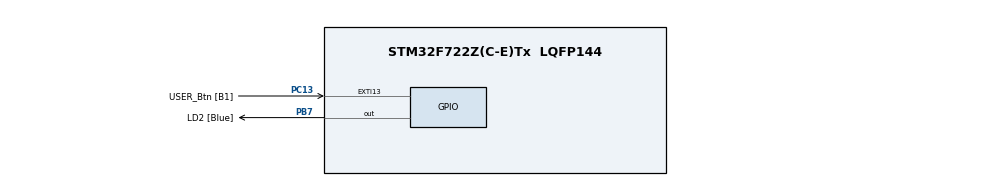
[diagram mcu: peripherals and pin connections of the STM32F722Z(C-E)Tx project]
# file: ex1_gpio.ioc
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Mcu.Family=STM32F7
Mcu.Name=STM32F722Z(C-E)Tx
Mcu.Package=LQFP144
NVIC.PriorityGroup=NVIC_PRIORITYGROUP_4
NVIC.TIM1_UP_TIM10_IRQn=true\:0\:0\:false\:false\:true\:false\:false
NVIC.TimeBase=TIM1_UP_TIM10_IRQn
NVIC.TimeBaseIP=TIM1
PB3.GPIO_Label=SWO
PB3.Signal=SYS_JTDO-SWO
PB7.GPIO_Label=LD2 [Blue]
PB7.Signal=GPIO_Output
PC13.GPIO_Label=USER_Btn [B1]
PC13.Signal=GPXTI13
ProjectManager.HeapSize=0x200
ProjectManager.StackSize=0x400
ProjectManager.TargetToolchain=SW4STM32
RCC.48MHZClocksFreq_Value=24000000
RCC.AHBFreq_Value=108000000
RCC.APB1CLKDivider=RCC_HCLK_DIV4
RCC.APB1Freq_Value=27000000
RCC.APB1TimFreq_Value=54000000
RCC.APB2CLKDivider=RCC_HCLK_DIV2
RCC.APB2Freq_Value=54000000
RCC.APB2TimFreq_Value=108000000
RCC.CortexFreq_Value=108000000
RCC.HCLKFreq_Value=108000000
RCC.HSE_VALUE=25000000
RCC.HSI_VALUE=16000000
RCC.PLLM=25
RCC.PLLMUL=RCC_PLL_MUL9
RCC.PLLN=432
RCC.PLLP=RCC_PLLP_DIV4
RCC.PLLQ=9
RCC.PRESCALERUSB=RCC_USBCLKSOURCE_PLL_DIV1_5
RCC.SYSCLKFreq_VALUE=108000000
RCC.SYSCLKSource=RCC_SYSCLKSOURCE_PLLCLK
RCC.SYSCLKSourceVirtual=RCC_SYSCLKSOURCE_PLLCLK
RCC.USBFreq_Value=48000000
RCC.VCOOutputFreq_Value=432000000
board=NUCLEO-F722ZE

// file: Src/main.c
/**
  ******************************************************************************
  * @file           : main.c
  * @brief          : Main program body
  ******************************************************************************
  ** This notice applies to any and all portions of this file
  * that are not between comment pairs USER CODE BEGIN and
  * USER CODE END. Other portions of this file, whether
  * inserted by the user or by software development tools
  * are owned by their respective copyright owners.
  *
  * COPYRIGHT(c) 2018 STMicroelectronics
  *
  * Redistribution and use in source and binary forms, with or without modification,
  * are permitted provided that the following conditions are met:
  *   1. Redistributions of source code must retain the above copyright notice,
  *      this list of conditions and the following disclaimer.
  *   2. Redistributions in binary form must reproduce the above copyright notice,
  *      this list of conditions and the following disclaimer in the documentation
  *      and/or other materials provided with the distribution.
  *   3. Neither the name of STMicroelectronics nor the names of its contributors
  *      may be used to endorse or promote products derived from this software
  *      without specific prior written permission.
  *
  * THIS SOFTWARE IS PROVIDED BY THE COPYRIGHT HOLDERS AND CONTRIBUTORS "AS IS"
  * AND ANY EXPRESS OR IMPLIED WARRANTIES, INCLUDING, BUT NOT LIMITED TO, THE
  * IMPLIED WARRANTIES OF MERCHANTABILITY AND FITNESS FOR A PARTICULAR PURPOSE ARE
  * DISCLAIMED. IN NO EVENT SHALL THE COPYRIGHT HOLDER OR CONTRIBUTORS BE LIABLE
  * FOR ANY DIRECT, INDIRECT, INCIDENTAL, SPECIAL, EXEMPLARY, OR CONSEQUENTIAL
  * DAMAGES (INCLUDING, BUT NOT LIMITED TO, PROCUREMENT OF SUBSTITUTE GOODS OR
  * SERVICES; LOSS OF USE, DATA, OR PROFITS; OR BUSINESS INTERRUPTION) HOWEVER
  * CAUSED AND ON ANY THEORY OF LIABILITY, WHETHER IN CONTRACT, STRICT LIABILITY,
  * OR TORT (INCLUDING NEGLIGENCE OR OTHERWISE) ARISING IN ANY WAY OUT OF THE USE
  * OF THIS SOFTWARE, EVEN IF ADVISED OF THE POSSIBILITY OF SUCH DAMAGE.
  *
  ******************************************************************************
  */
#include "main.h"
#include "stm32f7xx_hal.h"

/* USER CODE BEGIN PV */
/* Private variables ---------------------------------------------------------*/

/* USER CODE END PV */

void SystemClock_Config(void);
static void MX_GPIO_Init(void);

/* USER CODE BEGIN PFP */
/* Private function prototypes -----------------------------------------------*/

/* USER CODE END PFP */

int main(void)
{

  /* MCU Configuration----------------------------------------------------------*/

  /* Reset of all peripherals, Initializes the Flash interface and the Systick. */
  HAL_Init();

  /* Configure the system clock */
  SystemClock_Config();

  /* Initialize all configured peripherals */
  MX_GPIO_Init();
  /* USER CODE BEGIN 2 */
  __HAL_RCC_GPIOB_CLK_ENABLE();
  volatile uint32_t* GPIOB_MODER	= (uint32_t*)	0x40020400;
  volatile uint32_t* GPIOB_ODR		= (uint32_t*)	(0x40020400 + 0x14);
  /* USER CODE END 2 */
  *GPIOB_MODER  |= 0x200;
  *GPIOB_ODR	|= 0x80;
  /* Infinite loop */
  /* USER CODE BEGIN WHILE */

  while (1)
  {
	  *GPIOB_ODR	|= 0x80;
	  HAL_Delay(9000);
	  *GPIOB_ODR	&= 0x00;
  /* USER CODE END WHILE */

  }

}

void SystemClock_Config(void)
{

  RCC_OscInitTypeDef RCC_OscInitStruct;
  RCC_ClkInitTypeDef RCC_ClkInitStruct;

    /**Configure the main internal regulator output voltage
    */
  __HAL_RCC_PWR_CLK_ENABLE();

  __HAL_PWR_VOLTAGESCALING_CONFIG(PWR_REGULATOR_VOLTAGE_SCALE3);

    /**Initializes the CPU, AHB and APB busses clocks
    */
  RCC_OscInitStruct.OscillatorType = RCC_OSCILLATORTYPE_HSI;
  RCC_OscInitStruct.HSIState = RCC_HSI_ON;
  RCC_OscInitStruct.HSICalibrationValue = 16;
  RCC_OscInitStruct.PLL.PLLState = RCC_PLL_ON;
  RCC_OscInitStruct.PLL.PLLSource = RCC_PLLSOURCE_HSI;
  RCC_OscInitStruct.PLL.PLLM = 25;
  RCC_OscInitStruct.PLL.PLLN = 432;
  RCC_OscInitStruct.PLL.PLLP = RCC_PLLP_DIV4;
  RCC_OscInitStruct.PLL.PLLQ = 9;
  if (HAL_RCC_OscConfig(&RCC_OscInitStruct) != HAL_OK)
  {
    _Error_Handler(__FILE__, __LINE__);
  }

    /**Initializes the CPU, AHB and APB busses clocks
    */
  RCC_ClkInitStruct.ClockType = RCC_CLOCKTYPE_HCLK|RCC_CLOCKTYPE_SYSCLK
                              |RCC_CLOCKTYPE_PCLK1|RCC_CLOCKTYPE_PCLK2;
  RCC_ClkInitStruct.SYSCLKSource = RCC_SYSCLKSOURCE_PLLCLK;
  RCC_ClkInitStruct.AHBCLKDivider = RCC_SYSCLK_DIV1;
  RCC_ClkInitStruct.APB1CLKDivider = RCC_HCLK_DIV4;
  RCC_ClkInitStruct.APB2CLKDivider = RCC_HCLK_DIV2;

  if (HAL_RCC_ClockConfig(&RCC_ClkInitStruct, FLASH_LATENCY_3) != HAL_OK)
  {
    _Error_Handler(__FILE__, __LINE__);
  }

    /**Configure the Systick interrupt time
    */
  HAL_SYSTICK_Config(HAL_RCC_GetHCLKFreq()/1000);

    /**Configure the Systick
    */
  HAL_SYSTICK_CLKSourceConfig(SYSTICK_CLKSOURCE_HCLK);

  /* SysTick_IRQn interrupt configuration */
  HAL_NVIC_SetPriority(SysTick_IRQn, 15, 0);
}

/** Configure pins as
        * Analog
        * Input
        * Output
        * EVENT_OUT
        * EXTI
*/
static void MX_GPIO_Init(void)
{

  GPIO_InitTypeDef GPIO_InitStruct;

  /* GPIO Ports Clock Enable */
  __HAL_RCC_GPIOC_CLK_ENABLE();
  __HAL_RCC_GPIOB_CLK_ENABLE();

  /*Configure GPIO pin Output Level */
  HAL_GPIO_WritePin(LD2_GPIO_Port, LD2_Pin, GPIO_PIN_RESET);

  /*Configure GPIO pin : USER_Btn_Pin */
  GPIO_InitStruct.Pin = USER_Btn_Pin;
  GPIO_InitStruct.Mode = GPIO_MODE_IT_RISING;
  GPIO_InitStruct.Pull = GPIO_NOPULL;
  HAL_GPIO_Init(USER_Btn_GPIO_Port, &GPIO_InitStruct);

  /*Configure GPIO pin : LD2_Pin */
  GPIO_InitStruct.Pin = LD2_Pin;
  GPIO_InitStruct.Mode = GPIO_MODE_OUTPUT_PP;
  GPIO_InitStruct.Pull = GPIO_NOPULL;
  GPIO_InitStruct.Speed = GPIO_SPEED_FREQ_LOW;
  HAL_GPIO_Init(LD2_GPIO_Port, &GPIO_InitStruct);

}

void _Error_Handler(char *file, int line)
{
  while(1)
  {
  }
}

/************************ (C) COPYRIGHT STMicroelectronics *****END OF FILE****/
